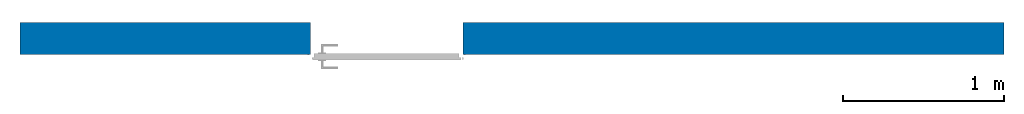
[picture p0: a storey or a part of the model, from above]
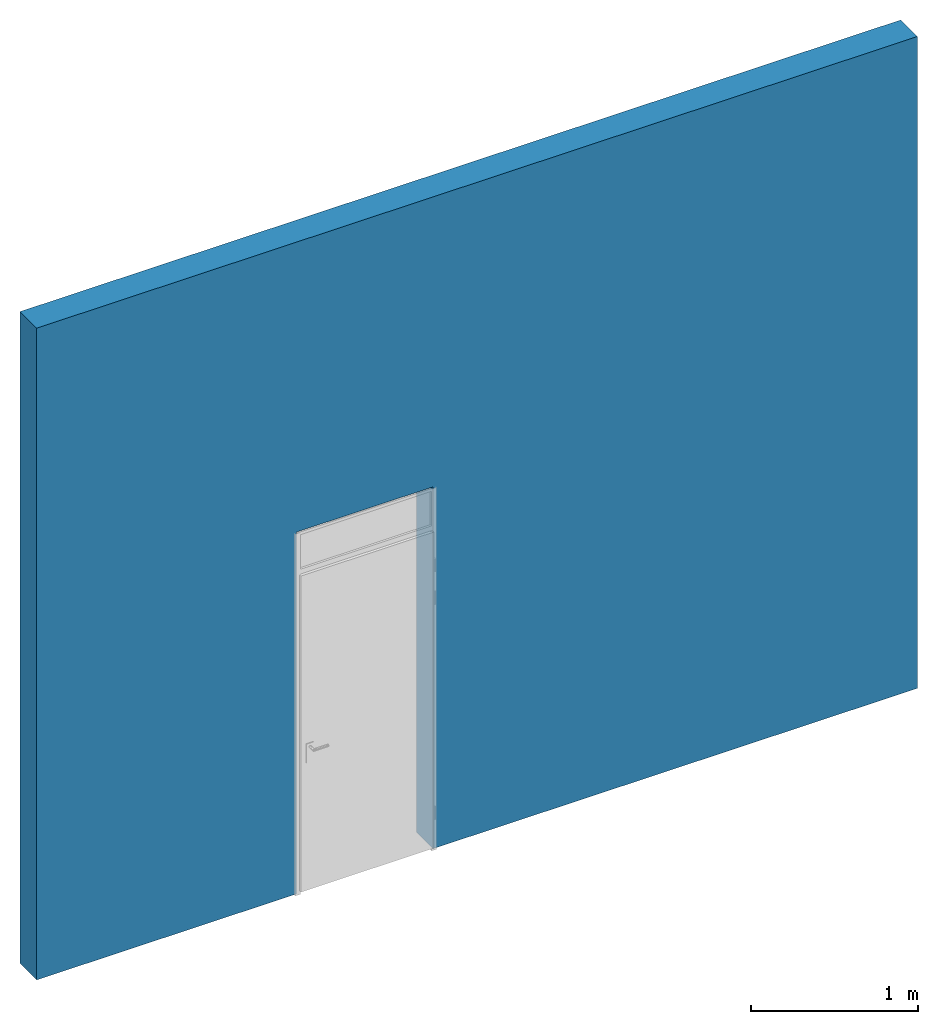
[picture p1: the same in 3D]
Properties of the parts of a building model (IFC2X3)

# File
Description: ViewDefinition [CoordinationView_V2.0]
File name: 0001
Time: 2018-10-11T11:42:01
Written by: The EXPRESS Data Manager Version 5.02.0100.07 : 28 Aug 2013
Made in: 20180328_1600(x64) - Exporter 19.1.0.0 - Alternate UI 19.1.0.0
Comment: STEP Physical File produced by: The EXPRESS Data Manager Version 5.02.0100.07 : 28 Aug 2013 * Module: EDMstepFileFactory/EDMstandAlone * Creation date: Thu Oct 11 11:42:01 2018 * Host: DESKTOP-FDA31SE * Database: C:\Users\marti\AppData\Local\Temp\{77AC1F04-C489-4CC4-BFF3-AE6A0B481E6D}\ifc * Database version: 5507 * Database creation date: Thu Oct 11 11:42:00 2018 * Schema: IFC2X3 * Model: DataRepository.ifc * Model creation date: Thu Oct 11 11:42:00 2018 * Header model: DataRepository.ifc_HeaderModel * Header model creation date: Thu Oct 11 11:42:00 2018 * EDMuser: sdai-user * EDMgroup: sdai-group * License ID and type: 5605 : Permanent license. Expiry date: * EDMstepFileFactory options: 020000

# IfcProject, 0001
LongName: Project Name; Phase: Project Status

# IfcSite, Default
RefLatitude: 42, 21, 30, 344238; RefLongitude: -71, -3, -35, -194702; RefElevation: 0 mm

# IfcBuilding, Building Name
LongName: Building Name
Pset_BuildingCommon - NumberOfStoreys: 1
Pset_ProductRequirements - Category: Project Information

# IfcBuildingStorey: Level:8mm Head, Level 1
In: Building Name
LongName: Level 1; Elevation: 0 mm
Pset_AirSideSystemInformation - Name: Level 1
Pset_ProductRequirements - Name: Level 1; Category: Levels

# IfcDoor: Berdo BA std_bxh 930X2315, IfcName
In: Level 1
Type - Description: IfcDescription; ParameterTakesPrecedence: no; Sizeable: no; Classification: 32.31 (Uniformat); Material: NLRS_o1_glas_helder, Berkvens <maak keuze>
OverallHeight: 2650 mm; OverallWidth: 945 mm
Pset_DoorCommon - Reference: -; IsExternal: no; FireExit: no; SmokeStop: no
Pset_ManufacturerTypeInformation - ModelReference: Berdo BA; ModelLabel: www.berkvens.nl; Manufacturer: Berkvens
Pset_ProductRequirements - Category: Doors
Pset_QuantityTakeOff - Reference: Berdo BA std_bxh 930X2315
UnifiedDoorProperties - UDP_RoomUnderDoor: 0.0918635; UDP_DoorHandleHeight: 3.44488; UDP_LockType: Berkvens BS210
RevitID - RevitID: 316620

# IfcWallStandardCase: Basic Wall:Generic - 200mm, Manual override for IfcName
In: Level 1
Type - Description: Manual override for IfcDescription; ElementType: Manual override for IfcElementType; PredefinedType: STANDARD; Material: Concrete, Cast In Situ 200 mm
Type - Pset_ConcreteElementGeneral - FireRating: Fire Rating
Type - Pset_ElementShading - Roughness: 914.4 mm
Type - Pset_ManufacturerTypeInformation - ModelReference: Model; Manufacturer: Manufacturer
Type - Pset_ProductRequirements - Category: Walls
Type - Pset_QuantityTakeOff - Reference: Generic - 200mm
Type - Pset_ReinforcementBarPitchOfWall - Description: Description; Reference: Generic - 200mm
Type - Pset_WallCommon - Reference: Description; FireRating: Fire Rating; ThermalTransmittance: 5.23 kg/K/s3; IsExternal: yes
Pset_WallCommon - ExtendToStructure: no; LoadBearing: no
